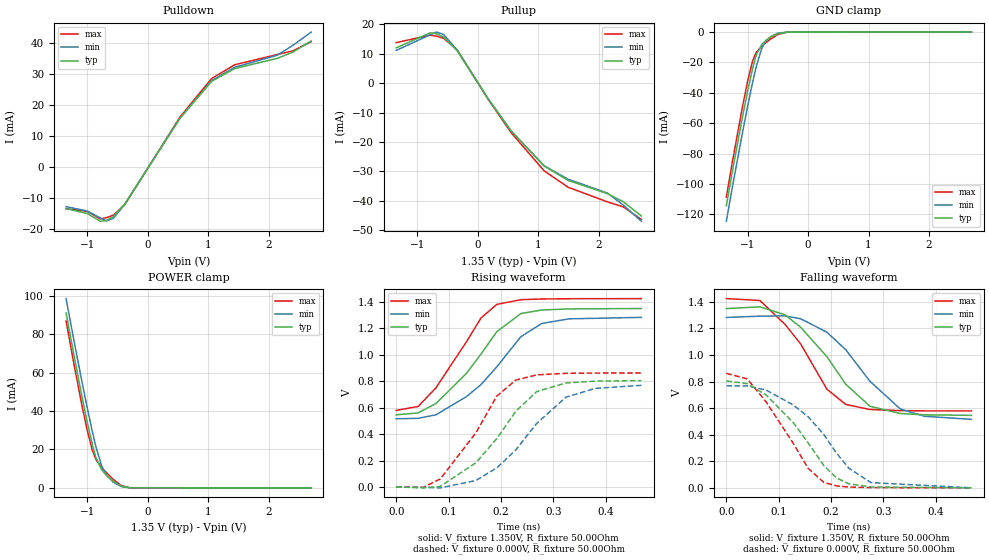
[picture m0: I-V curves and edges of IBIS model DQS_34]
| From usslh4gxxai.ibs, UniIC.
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| MODEL DQS_34 (34 Ohm Data Strobe I/O with no ODT, 800-2133Mbps)
[Model]   DQS_34
Model_type   I/O
Vinl = 545.000mV
Vinh = 805.000mV
Vmeas = 675.000mV
Vref = 675.000mV
Cref = 0.0pF
Rref = 25.000Ohm
|   typ   min   max
|C_comp   1.050pF   1.000pF   1.100pF
C_comp_pullup   0.5250pF   0.5000pF   0.5500pF
C_comp_pulldown   0.5250pF   0.5000pF   0.5500pF
[Model Spec]
| Input threshold voltage corners
Vinl   0.5450V   0.5115V   0.5825V
Vinh   0.8050V   0.7715V   0.8425V
| Measurement voltage corners
Vmeas   0.6750V   0.6415V   0.7125V
| Timing spec test load voltage corners
Vref   0.6750V   0.6415V   0.7125V
| Dynamic Overshoot Parameters from DDR3L Specification
|D_overshoot_ampl_h   0.40   NA   NA
|D_overshoot_ampl_l   0.40   NA   NA
|D_overshoot_area_h   0.11n   NA   NA
|D_overshoot_area_l   0.11n   NA   NA
[Receiver Thresholds]
|Vth   =  0.675V
|Vth_min  =  0.6615V
|Vth_max  =  0.6885V
|Vinh_ac  =  0.130V
|Vinh_dc  =  0.090V
|Vinl_ac  = -0.130V
|Vinl_dc  = -0.090V
|Tslew_ac =  5.000ns |Not specified, so set to high value
|Threshold_sensitivity = 0.50
|Reference_supply Pullup_ref
|NOTE: If using the IBISCHK 4.2.1 or older parser, Differential receiver
|threshold parameters must be commented out because the parser generates
|errors for multiple differential models.
Vcross_low   = 0.545V
Vcross_high  = 0.805V
Vdiff_ac   = 260mV
Vdiff_dc   = 180mV
Tdiffslew_ac = 10.000ns |Not specified, so set to high value
[Voltage Range]   1.3500V   1.2830V   1.4250V
[Pullup Reference]   1.3500V   1.2830V   1.4250V
[Temperature Range]   45.0   95.0   -40.0
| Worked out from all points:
|   slope of the pulldown table from 0 to 0.203 V, typ, clamps not added: 32.6 ohm
|   slope of the pullup table from 0 to 0.203 V, typ, clamps not added: 32.2 ohm
|   GND clamp passes 1 mA (typ) near -0.49 V on its own axis
|   POWER clamp passes 1 mA (typ) near -0.45 V on its own axis
|   falling waveform, V_fixture 1.350V, R_fixture 50.00Ohm: 20-80 % time 96.1ps typ, 99.3ps min, 84.6ps max; typ from 1.35 V to 0.546 V
|   rising waveform, V_fixture 1.350V, R_fixture 50.00Ohm: 20-80 % time 98.7ps typ, 106ps min, 82.4ps max; typ from 0.546 V to 1.35 V
|   rising waveform, V_fixture 0.000V, R_fixture 50.00Ohm: 20-80 % time 97.4ps typ, 105ps min, 83.3ps max; typ from 0 V to 0.805 V
|   falling waveform, V_fixture 0.000V, R_fixture 50.00Ohm: 20-80 % time 96.8ps typ, 102ps min, 82.8ps max; typ from 0.805 V to 0 V
[Pulldown]
|   Voltage   I(typ)   I(min)   I(max)
-1.35V    -13.34mA   -12.72mA   -13.37mA
-1V       -14.92mA   -14.12mA   -14.25mA
-785mV    -17.42mA   -16.34mA   -16.66mA
-685mV    -17.14mA   -17.33mA   -16.27mA
-570mV    -15.93mA   -16.47mA   -15.46mA
-385mV    -11.98mA   -12.09mA   -12.21mA
535mV     15.8mA     15.87mA    16.22mA
1.055V    27.62mA    27.85mA    28.52mA
1.435V    31.72mA    32.13mA    32.93mA
2.135V    34.98mA    35.99mA    36.23mA
2.4V      37.04mA    39.22mA    37.44mA
2.7V      40.59mA    43.47mA    40.39mA
[GND Clamp]
|   Voltage   I(typ)   I(min)   I(max)
-1.35V    -114.4mA   -124.6mA   -108.7mA
-1.25V    -91.71mA   -102mA     -85.41mA
-1.085V   -56.31mA   -66.65mA   -49.52mA
-1V       -39.18mA   -49.29mA   -32.6mA
-915mV    -23.97mA   -32.97mA   -18.78mA
-855mV    -15.04mA   -22.61mA   -13.29mA
-760mV    -7.865mA   -10.21mA   -9.074mA
-685mV    -5.148mA   -5.368mA   -6.619mA
-620mV    -3.44mA    -3.073mA   -4.651mA
-495mV    -1.044mA   -720uA     -1.571mA
-345mV    -90.02uA   -50.11uA   -74.67uA
2.7V      0A         0A         0A
[Pullup]
|   Voltage   I(typ)   I(min)   I(max)
-1.35V    12.01mA    11.13mA    13.78mA
-785mV    17.15mA    16.5mA     16.34mA
-685mV    16.79mA    17.38mA    15.97mA
-570mV    15.71mA    16.6mA     15.28mA
-345mV    11.06mA    11.33mA    11.39mA
165mV     -5.155mA   -5.209mA   -5.33mA
550mV     -16.21mA   -16.33mA   -16.87mA
1.095V    -28.19mA   -28.08mA   -29.82mA
1.49V     -33.05mA   -32.64mA   -35.37mA
2.14V     -37.57mA   -37.35mA   -40.35mA
2.4V      -40.28mA   -41.41mA   -42.04mA
2.7V      -45.13mA   -46.94mA   -46.32mA
[POWER Clamp]
|   Voltage   I(typ)   I(min)   I(max)
-1.35V    91.15mA    98.58mA    86.92mA
-1.21V    67.43mA    75.08mA    62.69mA
-1.085V   47.16mA    54.84mA    42.5mA
-1V       34.13mA    41.63mA    29.89mA
-915mV    22.48mA    29.16mA    19.36mA
-855mV    15.54mA    21.16mA    14.73mA
-760mV    9.343mA    11.27mA    10.55mA
-685mV    6.542mA    6.798mA    7.95mA
-570mV    3.396mA    2.887mA    4.347mA
-435mV    857.8uA    628.6uA    1.141mA
-305mV    50.49uA    49.73uA    60.5uA
2.7V      0A         0A         0A
[Ramp]
R_load = 50.00Ohm
|   typ   min   max
dV/dt_r   482.782mV/97.407ps  461.209mV/105.194ps 517.064mV/83.320ps
dV/dt_f   482.599mV/96.048ps  460.290mV/99.310ps  514.017mV/84.623ps
[Falling Waveform]
V_fixture = 1.350V
V_fixture_min = 1.283V
V_fixture_max = 1.425V
R_fixture = 50.00Ohm
|   Time   V(typ)   V(min)   V(max)
0s        1.35V      1.283V     1.425V
64ps      1.363V     1.293V     1.411V
112ps     1.303V     1.295V     1.231V
142ps     1.209V     1.273V     1.083V
192ps     987.7mV    1.172V     742.7mV
228ps     780.1mV    1.04V      627.9mV
274ps     614.6mV    803.1mV    590.1mV
332ps     559.6mV    594.2mV    581.3mV
378ps     550.1mV    538.9mV    579.6mV
468ps     545.7mV    515.9mV    579.1mV
[Rising Waveform]
V_fixture = 1.350V
V_fixture_min = 1.283V
V_fixture_max = 1.425V
R_fixture = 50.00Ohm
|   Time   V(typ)   V(min)   V(max)
0s        545.7mV    515.9mV    579.1mV
42ps      560.3mV    519.2mV    609.2mV
76ps      631.8mV    546.1mV    750.9mV
134ps     858.6mV    683.3mV    1.098V
162ps     1.006V     775mV      1.279V
192ps     1.175V     908.9mV    1.381V
238ps     1.312V     1.137V     1.417V
278ps     1.339V     1.237V     1.422V
330ps     1.347V     1.272V     1.424V
468ps     1.35V      1.283V     1.425V
[Rising Waveform]
V_fixture = 0.000V
V_fixture_min = 0.000V
V_fixture_max = 0.000V
R_fixture = 50.00Ohm
|   Time   V(typ)   V(min)   V(max)
0s        -23.08uV   -32.56uV   -10.46uV
52ps      -6.443mV   -4.241mV   -2.375mV
84ps      3.892mV    -6.617mV   60.1mV
152ps     182.8mV    48.66mV    409mV
192ps     365.6mV    144.6mV    687mV
228ps     571.1mV    278.9mV    808.1mV
268ps     721mV      480.1mV    848mV
324ps     786.8mV    679.1mV    859.7mV
380ps     800.7mV    745.9mV    861.8mV
468ps     804.6mV    768.7mV    862mV
[Falling Waveform]
V_fixture = 0.000V
V_fixture_min = 0.000V
V_fixture_max = 0.000V
R_fixture = 50.00Ohm
|   Time   V(typ)   V(min)   V(max)
0s        804.6mV    768.7mV    862mV
40ps      784.6mV    767mV      820.5mV
76ps      699.1mV    736.4mV    646.8mV
128ps     489.9mV    622.9mV    333.9mV
156ps     339.8mV    535.7mV    147.3mV
186ps     168.3mV    402.2mV    41.37mV
210ps     75.54mV    263mV      14.76mV
234ps     30.15mV    147.4mV    5.872mV
276ps     6.493mV    39.34mV    1.727mV
468ps     -23.08uV   -32.56uV   -10.46uV
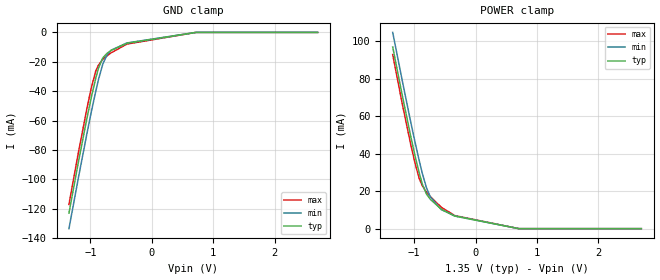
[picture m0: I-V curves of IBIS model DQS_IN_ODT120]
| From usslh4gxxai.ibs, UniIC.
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| MODEL DQS_IN_ODT120 (Data Strobe Input with 120ohm ODT, 800-2133Mbps)
[Model]   DQS_IN_ODT120
Model_type   Input
Vinl = 545.000mV
Vinh = 805.000mV
|   typ   min   max
|C_comp   1.049pF   0.999pF   1.094pF
C_comp_power_clamp   0.5245pF   0.4995pF   0.5470pF
C_comp_gnd_clamp   0.5245pF   0.4995pF   0.5470pF
| Note: C_comp changes when the ODT circuit is enabled.
[Model Spec]
| Input threshold voltage corners
Vinl   0.5450V   0.5115V   0.5825V
Vinh   0.8050V   0.7715V   0.8425V
| Dynamic Overshoot Parameters from DDR3L Specification
|D_overshoot_ampl_h   0.40   NA   NA
|D_overshoot_ampl_l   0.40   NA   NA
|D_overshoot_area_h   0.11n   NA   NA
|D_overshoot_area_l   0.11n   NA   NA
[Receiver Thresholds]
|Vth   =  0.675V
|Vth_min  =  0.6615V
|Vth_max  =  0.6885V
|Vinh_ac  =  0.130V
|Vinh_dc  =  0.090V
|Vinl_ac  = -0.130V
|Vinl_dc  = -0.090V
|Tslew_ac =  5.000ns |Not specified, so set to high value
|Threshold_sensitivity = 0.50
|Reference_supply Power_clamp_ref
|NOTE: If using the IBISCHK 4.2.1 or older parser, Differential receiver
|threshold parameters must be commented out because the parser generates
|errors for multiple differential models.
Vcross_low   = 0.545V
Vcross_high  = 0.805V
Vdiff_ac   = 260mV
Vdiff_dc   = 180mV
Tdiffslew_ac = 10.000ns |Not specified, so set to high value
[Voltage Range]   1.3500V   1.2830V   1.4250V
[POWER Clamp Reference]   1.3500V   1.2830V   1.4250V
[Temperature Range]   45.0   95.0   -40.0
[GND Clamp]
|   Voltage   I(typ)   I(min)   I(max)
-1.35V    -123mA     -133.6mA   -117.1mA
-1.195V   -88.01mA   -98.7mA    -81.49mA
-1.055V   -58.03mA   -68.41mA   -51.29mA
-985mV    -44.04mA   -53.96mA   -37.62mA
-915mV    -31.52mA   -40.39mA   -26.49mA
-870mV    -24.43mA   -32.23mA   -22.34mA
-800mV    -17.42mA   -21.76mA   -18.39mA
-730mV    -14.25mA   -15.3mA    -15.99mA
-665mV    -12.32mA   -12.16mA   -13.96mA
-405mV    -7.395mA   -7.167mA   -7.927mA
720mV     0A         0A         0A
2.7V      0A         0A         0A
[POWER Clamp]
|   Voltage   I(typ)   I(min)   I(max)
-1.35V    96.85mA    104.6mA    92.81mA
-1.195V   71.14mA    78.95mA    66.63mA
-1.055V   48.99mA    56.61mA    44.67mA
-985mV    38.64mA    45.92mA    34.73mA
-915mV    29.32mA    35.84mA    26.45mA
-870mV    24mA       29.74mA    23.05mA
-800mV    18.43mA    21.79mA    19.44mA
-735mV    15.56mA    16.79mA    17.07mA
-560mV    10.44mA    10.16mA    11.43mA
-340mV    6.725mA    6.783mA    6.985mA
705mV     0A         0A         0A
2.7V      0A         0A         0A
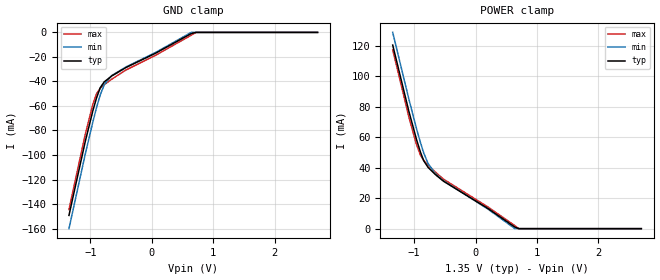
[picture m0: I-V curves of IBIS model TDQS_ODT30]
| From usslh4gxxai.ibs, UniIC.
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| MODEL TDQS_ODT30 (TDQS Terminator Model with 30ohm ODT, 800-2133Mbps)
[Model]   TDQS_ODT30
Model_type   Terminator
|   typ   min   max
|C_comp   0.989pF   0.938pF   1.051pF
C_comp_power_clamp   0.4945pF   0.4690pF   0.5255pF
C_comp_gnd_clamp   0.4945pF   0.4690pF   0.5255pF
| Note: C_comp changes when the ODT circuit is enabled.
[Voltage Range]   1.3500V   1.2830V   1.4250V
[Temperature Range]   45.0   95.0   -40.0
[GND Clamp]
|   Voltage   I(typ)   I(min)   I(max)
-1.35V    -149.3mA   -160.1mA   -144.5mA
-1.085V   -89.13mA   -99.43mA   -83.24mA
-960mV    -63.79mA   -72.88mA   -58.43mA
-900mV    -53.32mA   -61.2mA    -49.97mA
-840mV    -45.07mA   -50.91mA   -45.48mA
-775mV    -40.35mA   -42.64mA   -42.69mA
-655mV    -35.63mA   -35.25mA   -38.25mA
-425mV    -28.77mA   -28.28mA   -30.77mA
65mV      -16.87mA   -16.28mA   -18.57mA
640mV     -1.008mA   -45.78uA   -2.34mA
720mV     0A         0A         0A
2.7V      0A         0A         0A
[POWER Clamp]
|   Voltage   I(typ)   I(min)   I(max)
-1.35V    120.3mA    128.6mA    117.2mA
-1.085V   76.62mA    84.61mA    72.84mA
-965mV    58.82mA    65.95mA    55.43mA
-900mV    50.41mA    56.66mA    48.33mA
-845mV    44.56mA    49.63mA    44.71mA
-775mV    40.18mA    42.71mA    41.67mA
-655mV    35.46mA    36.07mA    37.1mA
-525mV    31.14mA    31.44mA    32.5mA
200mV     13.25mA    12.84mA    14.25mA
640mV     1.022mA    41.43uA    1.966mA
705mV     0A         0A         0A
2.7V      0A         0A         0A
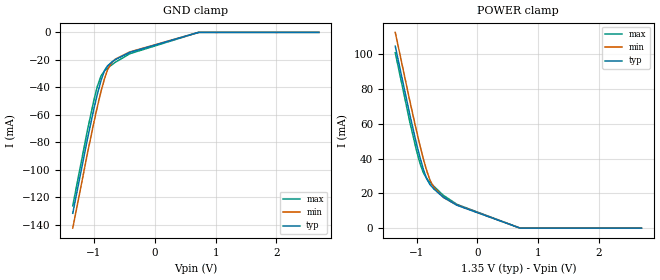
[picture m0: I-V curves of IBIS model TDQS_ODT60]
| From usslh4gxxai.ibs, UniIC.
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| MODEL TDQS_ODT60 (TDQS Terminator Model with 60ohm ODT, 800-2133Mbps)
[Model]   TDQS_ODT60
Model_type   Terminator
|   typ   min   max
|C_comp   0.962pF   0.911pF   1.017pF
C_comp_power_clamp   0.4810pF   0.4555pF   0.5085pF
C_comp_gnd_clamp   0.4810pF   0.4555pF   0.5085pF
| Note: C_comp changes when the ODT circuit is enabled.
[Voltage Range]   1.3500V   1.2830V   1.4250V
[Temperature Range]   45.0   95.0   -40.0
[GND Clamp]
|   Voltage   I(typ)   I(min)   I(max)
-1.35V    -131.8mA   -142.6mA   -126.3mA
-1.11V    -77.97mA   -88.53mA   -71.57mA
-1V       -55.11mA   -65.16mA   -48.92mA
-945mV    -45.04mA   -54.11mA   -39.28mA
-885mV    -35.01mA   -42.95mA   -31.73mA
-825mV    -27.52mA   -33.34mA   -27.93mA
-780mV    -24.5mA    -27.42mA   -26.15mA
-715mV    -21.84mA   -22.34mA   -23.89mA
-650mV    -19.84mA   -19.53mA   -21.78mA
-410mV    -14.49mA   -14.22mA   -15.53mA
720mV     0A         0A         0A
2.7V      0A         0A         0A
[POWER Clamp]
|   Voltage   I(typ)   I(min)   I(max)
-1.35V    104.7mA    112.7mA    101mA
-1.11V    65.25mA    73.14mA    61.03mA
-1V       48.43mA    55.95mA    44.61mA
-940mV    40.31mA    47.08mA    36.96mA
-885mV    33.51mA    39.51mA    31.67mA
-830mV    28.17mA    32.8mA     28.48mA
-780mV    25.15mA    27.73mA    26.46mA
-715mV    22.52mA    23.42mA    24.08mA
-560mV    17.79mA    17.7mA     18.9mA
-335mV    13.18mA    13.33mA    13.68mA
705mV     0A         0A         0A
2.7V      0A         0A         0A
